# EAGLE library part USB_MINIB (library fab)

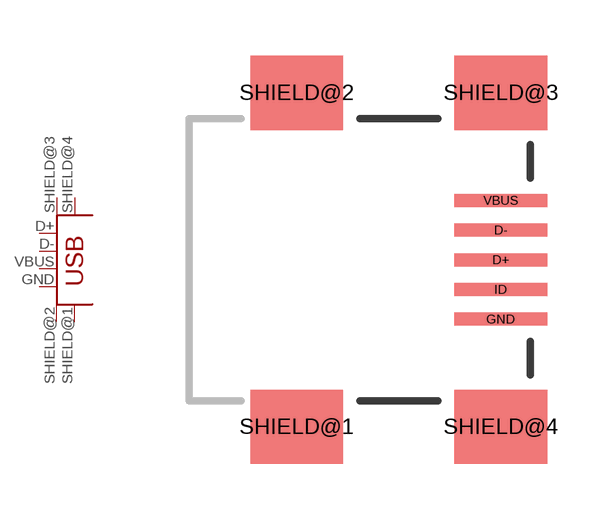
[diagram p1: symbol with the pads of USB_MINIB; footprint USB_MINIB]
Designator prefix -

## USB_MINIB  [USB_MINIB]
D+  D+
D-  D-
GND  GND
SHIELD@1  SHIELD  pas
SHIELD@2  SHIELD1  pas
SHIELD@3  SHIELD2  pas
SHIELD@4  SHIELD3  pas
VBUS  VBUS

## Footprint USB_MINIB (pad centres in mm)
smd 2.5 x 0.35: D+ 3.77,0; D- 3.77,0.8; GND 3.77,-1.6; ID 3.77,-0.8; VBUS 3.77,1.6
smd 2.5 x 2: SHIELD@1 -1.73,-4.5; SHIELD@2 -1.73,4.5; SHIELD@3 3.77,4.5; SHIELD@4 3.77,-4.5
